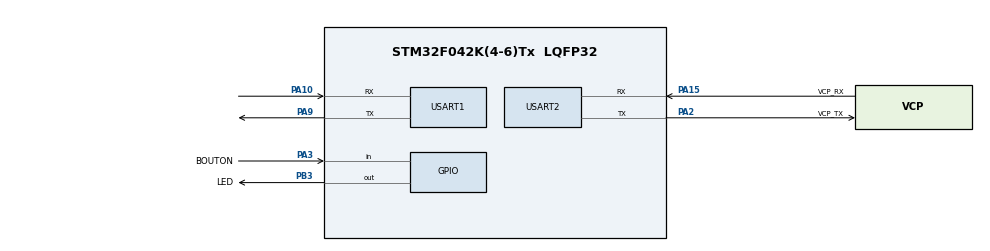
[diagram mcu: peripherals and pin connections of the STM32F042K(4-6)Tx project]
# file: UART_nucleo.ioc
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Mcu.Family=STM32F0
Mcu.Name=STM32F042K(4-6)Tx
Mcu.Package=LQFP32
PA10.Mode=Asynchronous
PA10.Signal=USART1_RX
PA13.GPIO_Label=SWDIO
PA13.Mode=Serial_Wire
PA13.Signal=SYS_SWDIO
PA14.GPIO_Label=SWCLK
PA14.Mode=Serial_Wire
PA14.Signal=SYS_SWCLK
PA15.GPIO_Label=VCP_RX
PA15.Mode=Asynchronous
PA15.Signal=USART2_RX
PA2.GPIO_Label=VCP_TX
PA2.Mode=Asynchronous
PA2.Signal=USART2_TX
PA3.GPIO_Label=BOUTON
PA3.Signal=GPIO_Input
PA9.Mode=Asynchronous
PA9.Signal=USART1_TX
PB3.GPIO_Label=LED
PB3.Signal=GPIO_Output
PF0-OSC_IN.GPIO_Label=MCO
PF0-OSC_IN.Mode=HSE-External-Clock-Source
PF0-OSC_IN.Signal=RCC_OSC_IN
ProjectManager.HeapSize=0x200
ProjectManager.StackSize=0x400
ProjectManager.TargetToolchain=Makefile
RCC.AHBFreq_Value=48000000
RCC.APB1Freq_Value=48000000
RCC.APB1TimFreq_Value=48000000
RCC.HCLKFreq_Value=48000000
RCC.PLLMUL=RCC_PLL_MUL6
RCC.PLLSourceVirtual=RCC_PLLSOURCE_HSE
RCC.SYSCLKFreq_VALUE=48000000
RCC.SYSCLKSource=RCC_SYSCLKSOURCE_PLLCLK
USART1.VirtualMode-Asynchronous=VM_ASYNC
USART2.VirtualMode-Asynchronous=VM_ASYNC
board=NUCLEO-F042K6

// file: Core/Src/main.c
/* USER CODE BEGIN Header */
/**
  ******************************************************************************
  * @file           : main.c
  * @brief          : Main program body
  ******************************************************************************
  * @attention
  *
  * <h2><center>&copy; Copyright (c) 2021 STMicroelectronics.
  * All rights reserved.</center></h2>
  *
  * This software component is licensed by ST under BSD 3-Clause license,
  * the "License"; You may not use this file except in compliance with the
  * License. You may obtain a copy of the License at:
  *                        opensource.org/licenses/BSD-3-Clause
  *
  ******************************************************************************
  */
/* USER CODE END Header */
#include "main.h"
#include "usart.h"
#include "gpio.h"

/* USER CODE BEGIN PV */
uint8_t  buffer = 2;
/* USER CODE END PV */

void SystemClock_Config(void);

int main(void)
{

  /* MCU Configuration--------------------------------------------------------*/

  /* Reset of all peripherals, Initializes the Flash interface and the Systick. */
  HAL_Init();

  /* Configure the system clock */
  SystemClock_Config();

  /* Initialize all configured peripherals */
  MX_GPIO_Init();
  MX_USART1_UART_Init();
  MX_USART2_UART_Init();
  /* USER CODE BEGIN 2 */
  HAL_GPIO_TogglePin(LED_GPIO_Port,LED_Pin);
  HAL_Delay(100);
  HAL_GPIO_TogglePin(LED_GPIO_Port,LED_Pin);
  /* USER CODE END 2 */

  /* Infinite loop */
  while (1)
  {

    /* USER CODE BEGIN 3 */
    if (!HAL_GPIO_ReadPin(BOUTON_GPIO_Port,BOUTON_Pin))
    {
    HAL_GPIO_TogglePin(LED_GPIO_Port,LED_Pin);
    HAL_UART_Transmit(&huart1,&buffer,sizeof(buffer),100);
    HAL_Delay(500);
    }else{
      HAL_GPIO_TogglePin(LED_GPIO_Port,LED_Pin);
    }
  }
  /* USER CODE END 3 */
}

void SystemClock_Config(void)
{
  RCC_OscInitTypeDef RCC_OscInitStruct = {0};
  RCC_ClkInitTypeDef RCC_ClkInitStruct = {0};
  RCC_PeriphCLKInitTypeDef PeriphClkInit = {0};

  /** Initializes the RCC Oscillators according to the specified parameters
  * in the RCC_OscInitTypeDef structure.
  */
 RCC_OscInitStruct.OscillatorType = RCC_OSCILLATORTYPE_HSI|RCC_OSCILLATORTYPE_HSI14
                              |RCC_OSCILLATORTYPE_HSI48;
  RCC_OscInitStruct.HSIState = RCC_HSI_ON;
  RCC_OscInitStruct.HSI48State = RCC_HSI48_ON;
  RCC_OscInitStruct.HSI14State = RCC_HSI14_ON;
  RCC_OscInitStruct.HSICalibrationValue = RCC_HSICALIBRATION_DEFAULT;
  RCC_OscInitStruct.HSI14CalibrationValue = 16;
  RCC_OscInitStruct.PLL.PLLState = RCC_PLL_NONE;
  if (HAL_RCC_OscConfig(&RCC_OscInitStruct) != HAL_OK)
  {
    Error_Handler();
  }
  /** Initializes the CPU, AHB and APB buses clocks
  */
  RCC_ClkInitStruct.ClockType = RCC_CLOCKTYPE_HCLK|RCC_CLOCKTYPE_SYSCLK
                              |RCC_CLOCKTYPE_PCLK1;
  RCC_ClkInitStruct.SYSCLKSource = RCC_SYSCLKSOURCE_HSI48;
  RCC_ClkInitStruct.AHBCLKDivider = RCC_SYSCLK_DIV1;
  RCC_ClkInitStruct.APB1CLKDivider = RCC_HCLK_DIV1;

  if (HAL_RCC_ClockConfig(&RCC_ClkInitStruct, FLASH_LATENCY_1) != HAL_OK)
  {
    Error_Handler();
  }
  PeriphClkInit.PeriphClockSelection = RCC_PERIPHCLK_USART1;
  PeriphClkInit.Usart1ClockSelection = RCC_USART1CLKSOURCE_PCLK1;
  if (HAL_RCCEx_PeriphCLKConfig(&PeriphClkInit) != HAL_OK)
  {
    Error_Handler();
  }
}

void Error_Handler(void)
{
  __disable_irq();
  while (1)
  {
  }
}

/************************ (C) COPYRIGHT STMicroelectronics *****END OF FILE****/
